VERSION 5.7 ;
  NOWIREEXTENSIONATPIN ON ;
  DIVIDERCHAR "/" ;
  BUSBITCHARS "[]" ;
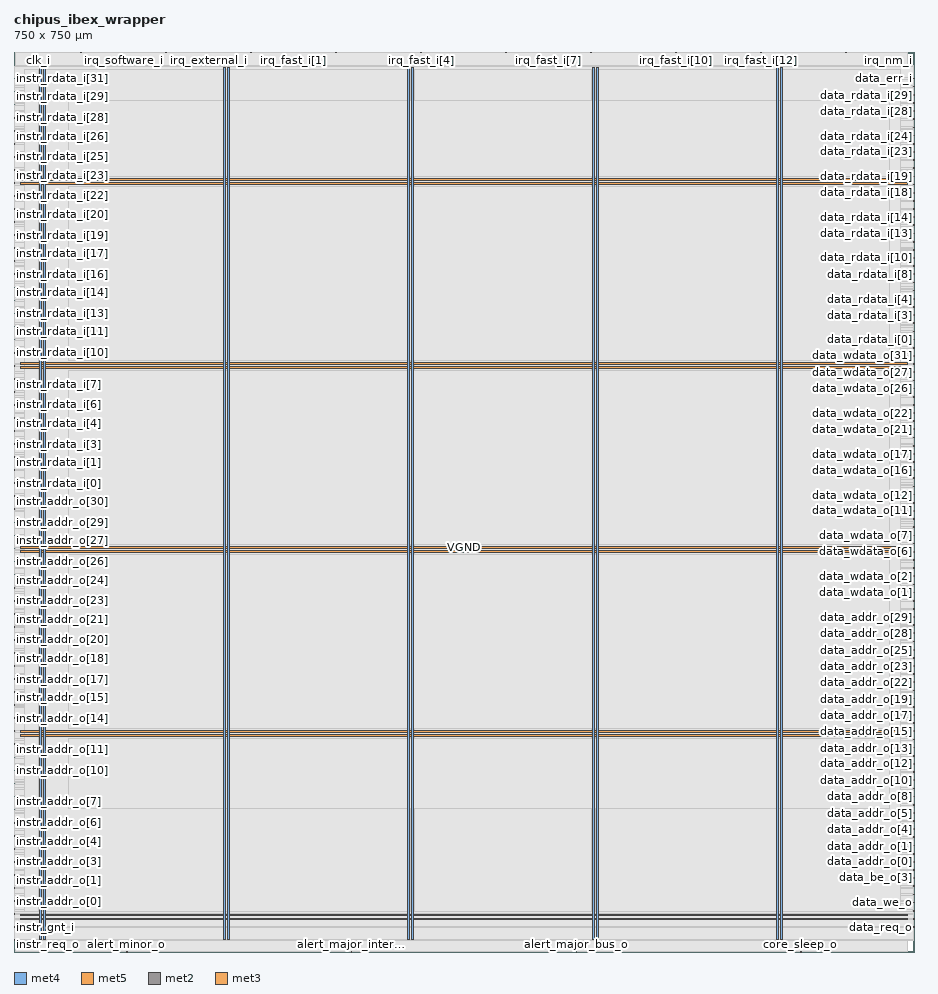
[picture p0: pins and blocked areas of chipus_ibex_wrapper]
MACRO chipus_ibex_wrapper
  CLASS BLOCK ;
  FOREIGN chipus_ibex_wrapper ;
  ORIGIN 0.000 0.000 ;
  SIZE 750.000 BY 750.000 ;
  PIN VGND
    DIRECTION INOUT ;
    USE GROUND ;
    PORT
      LAYER met4 ;
        RECT 24.340 10.640 25.940 737.360 ;
    END
    PORT
      LAYER met4 ;
        RECT 177.940 10.640 179.540 737.360 ;
    END
    PORT
      LAYER met4 ;
        RECT 331.540 10.640 333.140 737.360 ;
    END
    PORT
      LAYER met4 ;
        RECT 485.140 10.640 486.740 737.360 ;
    END
    PORT
      LAYER met4 ;
        RECT 638.740 10.640 640.340 737.360 ;
    END
    PORT
      LAYER met5 ;
        RECT 5.520 30.030 744.280 31.630 ;
    END
    PORT
      LAYER met5 ;
        RECT 5.520 183.210 744.280 184.810 ;
    END
    PORT
      LAYER met5 ;
        RECT 5.520 336.390 744.280 337.990 ;
    END
    PORT
      LAYER met5 ;
        RECT 5.520 489.570 744.280 491.170 ;
    END
    PORT
      LAYER met5 ;
        RECT 5.520 642.750 744.280 644.350 ;
    END
  END VGND
  PIN VPWR
    DIRECTION INOUT ;
    USE POWER ;
    PORT
      LAYER met4 ;
        RECT 21.040 10.640 22.640 737.360 ;
    END
    PORT
      LAYER met4 ;
        RECT 174.640 10.640 176.240 737.360 ;
    END
    PORT
      LAYER met4 ;
        RECT 328.240 10.640 329.840 737.360 ;
    END
    PORT
      LAYER met4 ;
        RECT 481.840 10.640 483.440 737.360 ;
    END
    PORT
      LAYER met4 ;
        RECT 635.440 10.640 637.040 737.360 ;
    END
    PORT
      LAYER met5 ;
        RECT 5.520 26.730 744.280 28.330 ;
    END
    PORT
      LAYER met5 ;
        RECT 5.520 179.910 744.280 181.510 ;
    END
    PORT
      LAYER met5 ;
        RECT 5.520 333.090 744.280 334.690 ;
    END
    PORT
      LAYER met5 ;
        RECT 5.520 486.270 744.280 487.870 ;
    END
    PORT
      LAYER met5 ;
        RECT 5.520 639.450 744.280 641.050 ;
    END
  END VPWR
  PIN alert_major_bus_o
    DIRECTION OUTPUT ;
    USE SIGNAL ;
    PORT
      LAYER met2 ;
        RECT 468.370 0.000 468.650 0.280 ;
    END
  END alert_major_bus_o
  PIN alert_major_internal_o
    DIRECTION OUTPUT ;
    USE SIGNAL ;
    PORT
      LAYER met2 ;
        RECT 281.150 0.000 281.430 0.280 ;
    END
  END alert_major_internal_o
  PIN alert_minor_o
    DIRECTION OUTPUT ;
    USE SIGNAL ;
    PORT
      LAYER met2 ;
        RECT 93.930 0.000 94.210 0.280 ;
    END
  END alert_minor_o
  PIN clk_i
    DIRECTION INPUT ;
    USE SIGNAL ;
    ANTENNAGATEAREA 1.704000 ;
    PORT
      LAYER met2 ;
        RECT 20.330 749.720 20.610 750.000 ;
    END
  END clk_i
  PIN core_sleep_o
    DIRECTION OUTPUT ;
    USE SIGNAL ;
    ANTENNADIFFAREA 0.702900 ;
    PORT
      LAYER met2 ;
        RECT 655.590 0.000 655.870 0.280 ;
    END
  END core_sleep_o
  PIN data_addr_o[0]
    DIRECTION OUTPUT ;
    USE SIGNAL ;
    PORT
      LAYER met3 ;
        RECT 749.400 74.840 750.000 75.440 ;
    END
  END data_addr_o[0]
  PIN data_addr_o[10]
    DIRECTION OUTPUT ;
    USE SIGNAL ;
    ANTENNADIFFAREA 0.702900 ;
    PORT
      LAYER met3 ;
        RECT 749.400 142.840 750.000 143.440 ;
    END
  END data_addr_o[10]
  PIN data_addr_o[11]
    DIRECTION OUTPUT ;
    USE SIGNAL ;
    ANTENNADIFFAREA 0.702900 ;
    PORT
      LAYER met3 ;
        RECT 749.400 149.640 750.000 150.240 ;
    END
  END data_addr_o[11]
  PIN data_addr_o[12]
    DIRECTION OUTPUT ;
    USE SIGNAL ;
    ANTENNADIFFAREA 0.702900 ;
    PORT
      LAYER met3 ;
        RECT 749.400 156.440 750.000 157.040 ;
    END
  END data_addr_o[12]
  PIN data_addr_o[13]
    DIRECTION OUTPUT ;
    USE SIGNAL ;
    ANTENNADIFFAREA 0.702900 ;
    PORT
      LAYER met3 ;
        RECT 749.400 163.240 750.000 163.840 ;
    END
  END data_addr_o[13]
  PIN data_addr_o[14]
    DIRECTION OUTPUT ;
    USE SIGNAL ;
    ANTENNADIFFAREA 0.702900 ;
    PORT
      LAYER met3 ;
        RECT 749.400 170.040 750.000 170.640 ;
    END
  END data_addr_o[14]
  PIN data_addr_o[15]
    DIRECTION OUTPUT ;
    USE SIGNAL ;
    ANTENNADIFFAREA 0.702900 ;
    PORT
      LAYER met3 ;
        RECT 749.400 176.840 750.000 177.440 ;
    END
  END data_addr_o[15]
  PIN data_addr_o[16]
    DIRECTION OUTPUT ;
    USE SIGNAL ;
    ANTENNADIFFAREA 0.702900 ;
    PORT
      LAYER met3 ;
        RECT 749.400 183.640 750.000 184.240 ;
    END
  END data_addr_o[16]
  PIN data_addr_o[17]
    DIRECTION OUTPUT ;
    USE SIGNAL ;
    ANTENNADIFFAREA 0.702900 ;
    PORT
      LAYER met3 ;
        RECT 749.400 190.440 750.000 191.040 ;
    END
  END data_addr_o[17]
  PIN data_addr_o[18]
    DIRECTION OUTPUT ;
    USE SIGNAL ;
    ANTENNADIFFAREA 0.702900 ;
    PORT
      LAYER met3 ;
        RECT 749.400 197.240 750.000 197.840 ;
    END
  END data_addr_o[18]
  PIN data_addr_o[19]
    DIRECTION OUTPUT ;
    USE SIGNAL ;
    ANTENNADIFFAREA 0.702900 ;
    PORT
      LAYER met3 ;
        RECT 749.400 204.040 750.000 204.640 ;
    END
  END data_addr_o[19]
  PIN data_addr_o[1]
    DIRECTION OUTPUT ;
    USE SIGNAL ;
    PORT
      LAYER met3 ;
        RECT 749.400 81.640 750.000 82.240 ;
    END
  END data_addr_o[1]
  PIN data_addr_o[20]
    DIRECTION OUTPUT ;
    USE SIGNAL ;
    ANTENNADIFFAREA 0.702900 ;
    PORT
      LAYER met3 ;
        RECT 749.400 210.840 750.000 211.440 ;
    END
  END data_addr_o[20]
  PIN data_addr_o[21]
    DIRECTION OUTPUT ;
    USE SIGNAL ;
    ANTENNADIFFAREA 0.702900 ;
    PORT
      LAYER met3 ;
        RECT 749.400 217.640 750.000 218.240 ;
    END
  END data_addr_o[21]
  PIN data_addr_o[22]
    DIRECTION OUTPUT ;
    USE SIGNAL ;
    ANTENNADIFFAREA 0.702900 ;
    PORT
      LAYER met3 ;
        RECT 749.400 224.440 750.000 225.040 ;
    END
  END data_addr_o[22]
  PIN data_addr_o[23]
    DIRECTION OUTPUT ;
    USE SIGNAL ;
    ANTENNADIFFAREA 0.702900 ;
    PORT
      LAYER met3 ;
        RECT 749.400 231.240 750.000 231.840 ;
    END
  END data_addr_o[23]
  PIN data_addr_o[24]
    DIRECTION OUTPUT ;
    USE SIGNAL ;
    ANTENNADIFFAREA 0.702900 ;
    PORT
      LAYER met3 ;
        RECT 749.400 238.040 750.000 238.640 ;
    END
  END data_addr_o[24]
  PIN data_addr_o[25]
    DIRECTION OUTPUT ;
    USE SIGNAL ;
    ANTENNADIFFAREA 0.702900 ;
    PORT
      LAYER met3 ;
        RECT 749.400 244.840 750.000 245.440 ;
    END
  END data_addr_o[25]
  PIN data_addr_o[26]
    DIRECTION OUTPUT ;
    USE SIGNAL ;
    ANTENNADIFFAREA 0.702900 ;
    PORT
      LAYER met3 ;
        RECT 749.400 251.640 750.000 252.240 ;
    END
  END data_addr_o[26]
  PIN data_addr_o[27]
    DIRECTION OUTPUT ;
    USE SIGNAL ;
    ANTENNADIFFAREA 0.702900 ;
    PORT
      LAYER met3 ;
        RECT 749.400 258.440 750.000 259.040 ;
    END
  END data_addr_o[27]
  PIN data_addr_o[28]
    DIRECTION OUTPUT ;
    USE SIGNAL ;
    ANTENNADIFFAREA 0.702900 ;
    PORT
      LAYER met3 ;
        RECT 749.400 265.240 750.000 265.840 ;
    END
  END data_addr_o[28]
  PIN data_addr_o[29]
    DIRECTION OUTPUT ;
    USE SIGNAL ;
    ANTENNADIFFAREA 0.702900 ;
    PORT
      LAYER met3 ;
        RECT 749.400 272.040 750.000 272.640 ;
    END
  END data_addr_o[29]
  PIN data_addr_o[2]
    DIRECTION OUTPUT ;
    USE SIGNAL ;
    ANTENNADIFFAREA 0.702900 ;
    PORT
      LAYER met3 ;
        RECT 749.400 88.440 750.000 89.040 ;
    END
  END data_addr_o[2]
  PIN data_addr_o[30]
    DIRECTION OUTPUT ;
    USE SIGNAL ;
    ANTENNADIFFAREA 0.702900 ;
    PORT
      LAYER met3 ;
        RECT 749.400 278.840 750.000 279.440 ;
    END
  END data_addr_o[30]
  PIN data_addr_o[31]
    DIRECTION OUTPUT ;
    USE SIGNAL ;
    ANTENNADIFFAREA 0.702900 ;
    PORT
      LAYER met3 ;
        RECT 749.400 285.640 750.000 286.240 ;
    END
  END data_addr_o[31]
  PIN data_addr_o[3]
    DIRECTION OUTPUT ;
    USE SIGNAL ;
    ANTENNADIFFAREA 0.702900 ;
    PORT
      LAYER met3 ;
        RECT 749.400 95.240 750.000 95.840 ;
    END
  END data_addr_o[3]
  PIN data_addr_o[4]
    DIRECTION OUTPUT ;
    USE SIGNAL ;
    ANTENNADIFFAREA 0.702900 ;
    PORT
      LAYER met3 ;
        RECT 749.400 102.040 750.000 102.640 ;
    END
  END data_addr_o[4]
  PIN data_addr_o[5]
    DIRECTION OUTPUT ;
    USE SIGNAL ;
    ANTENNADIFFAREA 0.702900 ;
    PORT
      LAYER met3 ;
        RECT 749.400 108.840 750.000 109.440 ;
    END
  END data_addr_o[5]
  PIN data_addr_o[6]
    DIRECTION OUTPUT ;
    USE SIGNAL ;
    ANTENNADIFFAREA 0.702900 ;
    PORT
      LAYER met3 ;
        RECT 749.400 115.640 750.000 116.240 ;
    END
  END data_addr_o[6]
  PIN data_addr_o[7]
    DIRECTION OUTPUT ;
    USE SIGNAL ;
    ANTENNADIFFAREA 0.702900 ;
    PORT
      LAYER met3 ;
        RECT 749.400 122.440 750.000 123.040 ;
    END
  END data_addr_o[7]
  PIN data_addr_o[8]
    DIRECTION OUTPUT ;
    USE SIGNAL ;
    ANTENNADIFFAREA 0.702900 ;
    PORT
      LAYER met3 ;
        RECT 749.400 129.240 750.000 129.840 ;
    END
  END data_addr_o[8]
  PIN data_addr_o[9]
    DIRECTION OUTPUT ;
    USE SIGNAL ;
    ANTENNADIFFAREA 0.702900 ;
    PORT
      LAYER met3 ;
        RECT 749.400 136.040 750.000 136.640 ;
    END
  END data_addr_o[9]
  PIN data_be_o[0]
    DIRECTION OUTPUT ;
    USE SIGNAL ;
    ANTENNADIFFAREA 0.702900 ;
    PORT
      LAYER met3 ;
        RECT 749.400 47.640 750.000 48.240 ;
    END
  END data_be_o[0]
  PIN data_be_o[1]
    DIRECTION OUTPUT ;
    USE SIGNAL ;
    ANTENNADIFFAREA 0.702900 ;
    PORT
      LAYER met3 ;
        RECT 749.400 54.440 750.000 55.040 ;
    END
  END data_be_o[1]
  PIN data_be_o[2]
    DIRECTION OUTPUT ;
    USE SIGNAL ;
    ANTENNADIFFAREA 0.702900 ;
    PORT
      LAYER met3 ;
        RECT 749.400 61.240 750.000 61.840 ;
    END
  END data_be_o[2]
  PIN data_be_o[3]
    DIRECTION OUTPUT ;
    USE SIGNAL ;
    ANTENNADIFFAREA 0.702900 ;
    PORT
      LAYER met3 ;
        RECT 749.400 68.040 750.000 68.640 ;
    END
  END data_be_o[3]
  PIN data_err_i
    DIRECTION INPUT ;
    USE SIGNAL ;
    ANTENNAGATEAREA 0.159000 ;
    PORT
      LAYER met3 ;
        RECT 749.400 727.640 750.000 728.240 ;
    END
  END data_err_i
  PIN data_gnt_i
    DIRECTION INPUT ;
    USE SIGNAL ;
    ANTENNAGATEAREA 0.159000 ;
    PORT
      LAYER met3 ;
        RECT 749.400 27.240 750.000 27.840 ;
    END
  END data_gnt_i
  PIN data_rdata_i[0]
    DIRECTION INPUT ;
    USE SIGNAL ;
    ANTENNAGATEAREA 0.213000 ;
    PORT
      LAYER met3 ;
        RECT 749.400 510.040 750.000 510.640 ;
    END
  END data_rdata_i[0]
  PIN data_rdata_i[10]
    DIRECTION INPUT ;
    USE SIGNAL ;
    ANTENNAGATEAREA 0.213000 ;
    PORT
      LAYER met3 ;
        RECT 749.400 578.040 750.000 578.640 ;
    END
  END data_rdata_i[10]
  PIN data_rdata_i[11]
    DIRECTION INPUT ;
    USE SIGNAL ;
    ANTENNAGATEAREA 0.213000 ;
    PORT
      LAYER met3 ;
        RECT 749.400 584.840 750.000 585.440 ;
    END
  END data_rdata_i[11]
  PIN data_rdata_i[12]
    DIRECTION INPUT ;
    USE SIGNAL ;
    ANTENNAGATEAREA 0.213000 ;
    PORT
      LAYER met3 ;
        RECT 749.400 591.640 750.000 592.240 ;
    END
  END data_rdata_i[12]
  PIN data_rdata_i[13]
    DIRECTION INPUT ;
    USE SIGNAL ;
    ANTENNAGATEAREA 0.213000 ;
    PORT
      LAYER met3 ;
        RECT 749.400 598.440 750.000 599.040 ;
    END
  END data_rdata_i[13]
  PIN data_rdata_i[14]
    DIRECTION INPUT ;
    USE SIGNAL ;
    ANTENNAGATEAREA 0.213000 ;
    PORT
      LAYER met3 ;
        RECT 749.400 605.240 750.000 605.840 ;
    END
  END data_rdata_i[14]
  PIN data_rdata_i[15]
    DIRECTION INPUT ;
    USE SIGNAL ;
    ANTENNAGATEAREA 0.213000 ;
    PORT
      LAYER met3 ;
        RECT 749.400 612.040 750.000 612.640 ;
    END
  END data_rdata_i[15]
  PIN data_rdata_i[16]
    DIRECTION INPUT ;
    USE SIGNAL ;
    ANTENNAGATEAREA 0.213000 ;
    PORT
      LAYER met3 ;
        RECT 749.400 618.840 750.000 619.440 ;
    END
  END data_rdata_i[16]
  PIN data_rdata_i[17]
    DIRECTION INPUT ;
    USE SIGNAL ;
    ANTENNAGATEAREA 0.213000 ;
    PORT
      LAYER met3 ;
        RECT 749.400 625.640 750.000 626.240 ;
    END
  END data_rdata_i[17]
  PIN data_rdata_i[18]
    DIRECTION INPUT ;
    USE SIGNAL ;
    ANTENNAGATEAREA 0.213000 ;
    PORT
      LAYER met3 ;
        RECT 749.400 632.440 750.000 633.040 ;
    END
  END data_rdata_i[18]
  PIN data_rdata_i[19]
    DIRECTION INPUT ;
    USE SIGNAL ;
    ANTENNAGATEAREA 0.213000 ;
    PORT
      LAYER met3 ;
        RECT 749.400 639.240 750.000 639.840 ;
    END
  END data_rdata_i[19]
  PIN data_rdata_i[1]
    DIRECTION INPUT ;
    USE SIGNAL ;
    ANTENNAGATEAREA 0.213000 ;
    PORT
      LAYER met3 ;
        RECT 749.400 516.840 750.000 517.440 ;
    END
  END data_rdata_i[1]
  PIN data_rdata_i[20]
    DIRECTION INPUT ;
    USE SIGNAL ;
    ANTENNAGATEAREA 0.213000 ;
    PORT
      LAYER met3 ;
        RECT 749.400 646.040 750.000 646.640 ;
    END
  END data_rdata_i[20]
  PIN data_rdata_i[21]
    DIRECTION INPUT ;
    USE SIGNAL ;
    ANTENNAGATEAREA 0.213000 ;
    PORT
      LAYER met3 ;
        RECT 749.400 652.840 750.000 653.440 ;
    END
  END data_rdata_i[21]
  PIN data_rdata_i[22]
    DIRECTION INPUT ;
    USE SIGNAL ;
    ANTENNAGATEAREA 0.213000 ;
    PORT
      LAYER met3 ;
        RECT 749.400 659.640 750.000 660.240 ;
    END
  END data_rdata_i[22]
  PIN data_rdata_i[23]
    DIRECTION INPUT ;
    USE SIGNAL ;
    ANTENNAGATEAREA 0.213000 ;
    PORT
      LAYER met3 ;
        RECT 749.400 666.440 750.000 667.040 ;
    END
  END data_rdata_i[23]
  PIN data_rdata_i[24]
    DIRECTION INPUT ;
    USE SIGNAL ;
    ANTENNAGATEAREA 0.213000 ;
    PORT
      LAYER met3 ;
        RECT 749.400 673.240 750.000 673.840 ;
    END
  END data_rdata_i[24]
  PIN data_rdata_i[25]
    DIRECTION INPUT ;
    USE SIGNAL ;
    ANTENNAGATEAREA 0.213000 ;
    PORT
      LAYER met3 ;
        RECT 749.400 680.040 750.000 680.640 ;
    END
  END data_rdata_i[25]
  PIN data_rdata_i[26]
    DIRECTION INPUT ;
    USE SIGNAL ;
    ANTENNAGATEAREA 0.213000 ;
    PORT
      LAYER met3 ;
        RECT 749.400 686.840 750.000 687.440 ;
    END
  END data_rdata_i[26]
  PIN data_rdata_i[27]
    DIRECTION INPUT ;
    USE SIGNAL ;
    ANTENNAGATEAREA 0.213000 ;
    PORT
      LAYER met3 ;
        RECT 749.400 693.640 750.000 694.240 ;
    END
  END data_rdata_i[27]
  PIN data_rdata_i[28]
    DIRECTION INPUT ;
    USE SIGNAL ;
    ANTENNAGATEAREA 0.213000 ;
    PORT
      LAYER met3 ;
        RECT 749.400 700.440 750.000 701.040 ;
    END
  END data_rdata_i[28]
  PIN data_rdata_i[29]
    DIRECTION INPUT ;
    USE SIGNAL ;
    ANTENNAGATEAREA 0.213000 ;
    PORT
      LAYER met3 ;
        RECT 749.400 707.240 750.000 707.840 ;
    END
  END data_rdata_i[29]
  PIN data_rdata_i[2]
    DIRECTION INPUT ;
    USE SIGNAL ;
    ANTENNAGATEAREA 0.213000 ;
    PORT
      LAYER met3 ;
        RECT 749.400 523.640 750.000 524.240 ;
    END
  END data_rdata_i[2]
  PIN data_rdata_i[30]
    DIRECTION INPUT ;
    USE SIGNAL ;
    ANTENNAGATEAREA 0.213000 ;
    PORT
      LAYER met3 ;
        RECT 749.400 714.040 750.000 714.640 ;
    END
  END data_rdata_i[30]
  PIN data_rdata_i[31]
    DIRECTION INPUT ;
    USE SIGNAL ;
    ANTENNAGATEAREA 0.213000 ;
    PORT
      LAYER met3 ;
        RECT 749.400 720.840 750.000 721.440 ;
    END
  END data_rdata_i[31]
  PIN data_rdata_i[3]
    DIRECTION INPUT ;
    USE SIGNAL ;
    ANTENNAGATEAREA 0.213000 ;
    PORT
      LAYER met3 ;
        RECT 749.400 530.440 750.000 531.040 ;
    END
  END data_rdata_i[3]
  PIN data_rdata_i[4]
    DIRECTION INPUT ;
    USE SIGNAL ;
    ANTENNAGATEAREA 0.213000 ;
    PORT
      LAYER met3 ;
        RECT 749.400 537.240 750.000 537.840 ;
    END
  END data_rdata_i[4]
  PIN data_rdata_i[5]
    DIRECTION INPUT ;
    USE SIGNAL ;
    ANTENNAGATEAREA 0.213000 ;
    PORT
      LAYER met3 ;
        RECT 749.400 544.040 750.000 544.640 ;
    END
  END data_rdata_i[5]
  PIN data_rdata_i[6]
    DIRECTION INPUT ;
    USE SIGNAL ;
    ANTENNAGATEAREA 0.213000 ;
    PORT
      LAYER met3 ;
        RECT 749.400 550.840 750.000 551.440 ;
    END
  END data_rdata_i[6]
  PIN data_rdata_i[7]
    DIRECTION INPUT ;
    USE SIGNAL ;
    ANTENNAGATEAREA 0.213000 ;
    PORT
      LAYER met3 ;
        RECT 749.400 557.640 750.000 558.240 ;
    END
  END data_rdata_i[7]
  PIN data_rdata_i[8]
    DIRECTION INPUT ;
    USE SIGNAL ;
    ANTENNAGATEAREA 0.213000 ;
    PORT
      LAYER met3 ;
        RECT 749.400 564.440 750.000 565.040 ;
    END
  END data_rdata_i[8]
  PIN data_rdata_i[9]
    DIRECTION INPUT ;
    USE SIGNAL ;
    ANTENNAGATEAREA 0.213000 ;
    PORT
      LAYER met3 ;
        RECT 749.400 571.240 750.000 571.840 ;
    END
  END data_rdata_i[9]
  PIN data_req_o
    DIRECTION OUTPUT ;
    USE SIGNAL ;
    ANTENNADIFFAREA 0.702900 ;
    PORT
      LAYER met3 ;
        RECT 749.400 20.440 750.000 21.040 ;
    END
  END data_req_o
  PIN data_rvalid_i
    DIRECTION INPUT ;
    USE SIGNAL ;
    ANTENNAGATEAREA 0.159000 ;
    PORT
      LAYER met3 ;
        RECT 749.400 34.040 750.000 34.640 ;
    END
  END data_rvalid_i
  PIN data_wdata_o[0]
    DIRECTION OUTPUT ;
    USE SIGNAL ;
    ANTENNADIFFAREA 0.702900 ;
    PORT
      LAYER met3 ;
        RECT 749.400 292.440 750.000 293.040 ;
    END
  END data_wdata_o[0]
  PIN data_wdata_o[10]
    DIRECTION OUTPUT ;
    USE SIGNAL ;
    ANTENNADIFFAREA 0.702900 ;
    PORT
      LAYER met3 ;
        RECT 749.400 360.440 750.000 361.040 ;
    END
  END data_wdata_o[10]
  PIN data_wdata_o[11]
    DIRECTION OUTPUT ;
    USE SIGNAL ;
    ANTENNADIFFAREA 0.702900 ;
    PORT
      LAYER met3 ;
        RECT 749.400 367.240 750.000 367.840 ;
    END
  END data_wdata_o[11]
  PIN data_wdata_o[12]
    DIRECTION OUTPUT ;
    USE SIGNAL ;
    ANTENNADIFFAREA 0.702900 ;
    PORT
      LAYER met3 ;
        RECT 749.400 374.040 750.000 374.640 ;
    END
  END data_wdata_o[12]
  PIN data_wdata_o[13]
    DIRECTION OUTPUT ;
    USE SIGNAL ;
    ANTENNADIFFAREA 0.702900 ;
    PORT
      LAYER met3 ;
        RECT 749.400 380.840 750.000 381.440 ;
    END
  END data_wdata_o[13]
  PIN data_wdata_o[14]
    DIRECTION OUTPUT ;
    USE SIGNAL ;
    ANTENNADIFFAREA 0.702900 ;
    PORT
      LAYER met3 ;
        RECT 749.400 387.640 750.000 388.240 ;
    END
  END data_wdata_o[14]
  PIN data_wdata_o[15]
    DIRECTION OUTPUT ;
    USE SIGNAL ;
    ANTENNADIFFAREA 0.702900 ;
    PORT
      LAYER met3 ;
        RECT 749.400 394.440 750.000 395.040 ;
    END
  END data_wdata_o[15]
  PIN data_wdata_o[16]
    DIRECTION OUTPUT ;
    USE SIGNAL ;
    ANTENNADIFFAREA 0.702900 ;
    PORT
      LAYER met3 ;
        RECT 749.400 401.240 750.000 401.840 ;
    END
  END data_wdata_o[16]
  PIN data_wdata_o[17]
    DIRECTION OUTPUT ;
    USE SIGNAL ;
    ANTENNADIFFAREA 0.702900 ;
    PORT
      LAYER met3 ;
        RECT 749.400 408.040 750.000 408.640 ;
    END
  END data_wdata_o[17]
  PIN data_wdata_o[18]
    DIRECTION OUTPUT ;
    USE SIGNAL ;
    ANTENNADIFFAREA 0.702900 ;
    PORT
      LAYER met3 ;
        RECT 749.400 414.840 750.000 415.440 ;
    END
  END data_wdata_o[18]
  PIN data_wdata_o[19]
    DIRECTION OUTPUT ;
    USE SIGNAL ;
    ANTENNADIFFAREA 0.702900 ;
    PORT
      LAYER met3 ;
        RECT 749.400 421.640 750.000 422.240 ;
    END
  END data_wdata_o[19]
  PIN data_wdata_o[1]
    DIRECTION OUTPUT ;
    USE SIGNAL ;
    ANTENNADIFFAREA 0.702900 ;
    PORT
      LAYER met3 ;
        RECT 749.400 299.240 750.000 299.840 ;
    END
  END data_wdata_o[1]
  PIN data_wdata_o[20]
    DIRECTION OUTPUT ;
    USE SIGNAL ;
    ANTENNADIFFAREA 0.702900 ;
    PORT
      LAYER met3 ;
        RECT 749.400 428.440 750.000 429.040 ;
    END
  END data_wdata_o[20]
  PIN data_wdata_o[21]
    DIRECTION OUTPUT ;
    USE SIGNAL ;
    ANTENNADIFFAREA 0.702900 ;
    PORT
      LAYER met3 ;
        RECT 749.400 435.240 750.000 435.840 ;
    END
  END data_wdata_o[21]
  PIN data_wdata_o[22]
    DIRECTION OUTPUT ;
    USE SIGNAL ;
    ANTENNADIFFAREA 0.702900 ;
    PORT
      LAYER met3 ;
        RECT 749.400 442.040 750.000 442.640 ;
    END
  END data_wdata_o[22]
  PIN data_wdata_o[23]
    DIRECTION OUTPUT ;
    USE SIGNAL ;
    ANTENNADIFFAREA 0.702900 ;
    PORT
      LAYER met3 ;
        RECT 749.400 448.840 750.000 449.440 ;
    END
  END data_wdata_o[23]
  PIN data_wdata_o[24]
    DIRECTION OUTPUT ;
    USE SIGNAL ;
    ANTENNADIFFAREA 0.702900 ;
    PORT
      LAYER met3 ;
        RECT 749.400 455.640 750.000 456.240 ;
    END
  END data_wdata_o[24]
  PIN data_wdata_o[25]
    DIRECTION OUTPUT ;
    USE SIGNAL ;
    ANTENNADIFFAREA 0.702900 ;
    PORT
      LAYER met3 ;
        RECT 749.400 462.440 750.000 463.040 ;
    END
  END data_wdata_o[25]
  PIN data_wdata_o[26]
    DIRECTION OUTPUT ;
    USE SIGNAL ;
    ANTENNADIFFAREA 0.702900 ;
    PORT
      LAYER met3 ;
        RECT 749.400 469.240 750.000 469.840 ;
    END
  END data_wdata_o[26]
  PIN data_wdata_o[27]
    DIRECTION OUTPUT ;
    USE SIGNAL ;
    ANTENNADIFFAREA 0.702900 ;
    PORT
      LAYER met3 ;
        RECT 749.400 476.040 750.000 476.640 ;
    END
  END data_wdata_o[27]
  PIN data_wdata_o[28]
    DIRECTION OUTPUT ;
    USE SIGNAL ;
    ANTENNADIFFAREA 0.702900 ;
    PORT
      LAYER met3 ;
        RECT 749.400 482.840 750.000 483.440 ;
    END
  END data_wdata_o[28]
  PIN data_wdata_o[29]
    DIRECTION OUTPUT ;
    USE SIGNAL ;
    ANTENNADIFFAREA 0.702900 ;
    PORT
      LAYER met3 ;
        RECT 749.400 489.640 750.000 490.240 ;
    END
  END data_wdata_o[29]
  PIN data_wdata_o[2]
    DIRECTION OUTPUT ;
    USE SIGNAL ;
    ANTENNADIFFAREA 0.702900 ;
    PORT
      LAYER met3 ;
        RECT 749.400 306.040 750.000 306.640 ;
    END
  END data_wdata_o[2]
  PIN data_wdata_o[30]
    DIRECTION OUTPUT ;
    USE SIGNAL ;
    ANTENNADIFFAREA 0.702900 ;
    PORT
      LAYER met3 ;
        RECT 749.400 496.440 750.000 497.040 ;
    END
  END data_wdata_o[30]
  PIN data_wdata_o[31]
    DIRECTION OUTPUT ;
    USE SIGNAL ;
    ANTENNADIFFAREA 0.702900 ;
    PORT
      LAYER met3 ;
        RECT 749.400 503.240 750.000 503.840 ;
    END
  END data_wdata_o[31]
  PIN data_wdata_o[3]
    DIRECTION OUTPUT ;
    USE SIGNAL ;
    ANTENNADIFFAREA 0.702900 ;
    PORT
      LAYER met3 ;
        RECT 749.400 312.840 750.000 313.440 ;
    END
  END data_wdata_o[3]
  PIN data_wdata_o[4]
    DIRECTION OUTPUT ;
    USE SIGNAL ;
    ANTENNADIFFAREA 0.702900 ;
    PORT
      LAYER met3 ;
        RECT 749.400 319.640 750.000 320.240 ;
    END
  END data_wdata_o[4]
  PIN data_wdata_o[5]
    DIRECTION OUTPUT ;
    USE SIGNAL ;
    ANTENNADIFFAREA 0.702900 ;
    PORT
      LAYER met3 ;
        RECT 749.400 326.440 750.000 327.040 ;
    END
  END data_wdata_o[5]
  PIN data_wdata_o[6]
    DIRECTION OUTPUT ;
    USE SIGNAL ;
    ANTENNADIFFAREA 0.702900 ;
    PORT
      LAYER met3 ;
        RECT 749.400 333.240 750.000 333.840 ;
    END
  END data_wdata_o[6]
  PIN data_wdata_o[7]
    DIRECTION OUTPUT ;
    USE SIGNAL ;
    ANTENNADIFFAREA 0.702900 ;
    PORT
      LAYER met3 ;
        RECT 749.400 340.040 750.000 340.640 ;
    END
  END data_wdata_o[7]
  PIN data_wdata_o[8]
    DIRECTION OUTPUT ;
    USE SIGNAL ;
    ANTENNADIFFAREA 0.702900 ;
    PORT
      LAYER met3 ;
        RECT 749.400 346.840 750.000 347.440 ;
    END
  END data_wdata_o[8]
  PIN data_wdata_o[9]
    DIRECTION OUTPUT ;
    USE SIGNAL ;
    ANTENNADIFFAREA 0.702900 ;
    PORT
      LAYER met3 ;
        RECT 749.400 353.640 750.000 354.240 ;
    END
  END data_wdata_o[9]
  PIN data_we_o
    DIRECTION OUTPUT ;
    USE SIGNAL ;
    ANTENNADIFFAREA 0.702900 ;
    PORT
      LAYER met3 ;
        RECT 749.400 40.840 750.000 41.440 ;
    END
  END data_we_o
  PIN instr_addr_o[0]
    DIRECTION OUTPUT ;
    USE SIGNAL ;
    PORT
      LAYER met3 ;
        RECT 0.000 42.200 0.600 42.800 ;
    END
  END instr_addr_o[0]
  PIN instr_addr_o[10]
    DIRECTION OUTPUT ;
    USE SIGNAL ;
    ANTENNADIFFAREA 0.702900 ;
    PORT
      LAYER met3 ;
        RECT 0.000 151.000 0.600 151.600 ;
    END
  END instr_addr_o[10]
  PIN instr_addr_o[11]
    DIRECTION OUTPUT ;
    USE SIGNAL ;
    ANTENNADIFFAREA 0.702900 ;
    PORT
      LAYER met3 ;
        RECT 0.000 161.880 0.600 162.480 ;
    END
  END instr_addr_o[11]
  PIN instr_addr_o[12]
    DIRECTION OUTPUT ;
    USE SIGNAL ;
    ANTENNADIFFAREA 0.702900 ;
    PORT
      LAYER met3 ;
        RECT 0.000 172.760 0.600 173.360 ;
    END
  END instr_addr_o[12]
  PIN instr_addr_o[13]
    DIRECTION OUTPUT ;
    USE SIGNAL ;
    ANTENNADIFFAREA 0.702900 ;
    PORT
      LAYER met3 ;
        RECT 0.000 183.640 0.600 184.240 ;
    END
  END instr_addr_o[13]
  PIN instr_addr_o[14]
    DIRECTION OUTPUT ;
    USE SIGNAL ;
    ANTENNADIFFAREA 0.702900 ;
    PORT
      LAYER met3 ;
        RECT 0.000 194.520 0.600 195.120 ;
    END
  END instr_addr_o[14]
  PIN instr_addr_o[15]
    DIRECTION OUTPUT ;
    USE SIGNAL ;
    ANTENNADIFFAREA 0.702900 ;
    PORT
      LAYER met3 ;
        RECT 0.000 205.400 0.600 206.000 ;
    END
  END instr_addr_o[15]
  PIN instr_addr_o[16]
    DIRECTION OUTPUT ;
    USE SIGNAL ;
    ANTENNADIFFAREA 0.702900 ;
    PORT
      LAYER met3 ;
        RECT 0.000 216.280 0.600 216.880 ;
    END
  END instr_addr_o[16]
  PIN instr_addr_o[17]
    DIRECTION OUTPUT ;
    USE SIGNAL ;
    ANTENNADIFFAREA 0.702900 ;
    PORT
      LAYER met3 ;
        RECT 0.000 227.160 0.600 227.760 ;
    END
  END instr_addr_o[17]
  PIN instr_addr_o[18]
    DIRECTION OUTPUT ;
    USE SIGNAL ;
    ANTENNADIFFAREA 0.702900 ;
    PORT
      LAYER met3 ;
        RECT 0.000 238.040 0.600 238.640 ;
    END
  END instr_addr_o[18]
  PIN instr_addr_o[19]
    DIRECTION OUTPUT ;
    USE SIGNAL ;
    ANTENNADIFFAREA 0.702900 ;
    PORT
      LAYER met3 ;
        RECT 0.000 248.920 0.600 249.520 ;
    END
  END instr_addr_o[19]
  PIN instr_addr_o[1]
    DIRECTION OUTPUT ;
    USE SIGNAL ;
    PORT
      LAYER met3 ;
        RECT 0.000 53.080 0.600 53.680 ;
    END
  END instr_addr_o[1]
  PIN instr_addr_o[20]
    DIRECTION OUTPUT ;
    USE SIGNAL ;
    ANTENNADIFFAREA 0.702900 ;
    PORT
      LAYER met3 ;
        RECT 0.000 259.800 0.600 260.400 ;
    END
  END instr_addr_o[20]
  PIN instr_addr_o[21]
    DIRECTION OUTPUT ;
    USE SIGNAL ;
    ANTENNADIFFAREA 0.702900 ;
    PORT
      LAYER met3 ;
        RECT 0.000 270.680 0.600 271.280 ;
    END
  END instr_addr_o[21]
  PIN instr_addr_o[22]
    DIRECTION OUTPUT ;
    USE SIGNAL ;
    ANTENNADIFFAREA 0.702900 ;
    PORT
      LAYER met3 ;
        RECT 0.000 281.560 0.600 282.160 ;
    END
  END instr_addr_o[22]
  PIN instr_addr_o[23]
    DIRECTION OUTPUT ;
    USE SIGNAL ;
    ANTENNADIFFAREA 0.702900 ;
    PORT
      LAYER met3 ;
        RECT 0.000 292.440 0.600 293.040 ;
    END
  END instr_addr_o[23]
  PIN instr_addr_o[24]
    DIRECTION OUTPUT ;
    USE SIGNAL ;
    ANTENNADIFFAREA 0.702900 ;
    PORT
      LAYER met3 ;
        RECT 0.000 303.320 0.600 303.920 ;
    END
  END instr_addr_o[24]
  PIN instr_addr_o[25]
    DIRECTION OUTPUT ;
    USE SIGNAL ;
    ANTENNADIFFAREA 0.702900 ;
    PORT
      LAYER met3 ;
        RECT 0.000 314.200 0.600 314.800 ;
    END
  END instr_addr_o[25]
  PIN instr_addr_o[26]
    DIRECTION OUTPUT ;
    USE SIGNAL ;
    ANTENNADIFFAREA 0.702900 ;
    PORT
      LAYER met3 ;
        RECT 0.000 325.080 0.600 325.680 ;
    END
  END instr_addr_o[26]
  PIN instr_addr_o[27]
    DIRECTION OUTPUT ;
    USE SIGNAL ;
    ANTENNADIFFAREA 0.702900 ;
    PORT
      LAYER met3 ;
        RECT 0.000 335.960 0.600 336.560 ;
    END
  END instr_addr_o[27]
  PIN instr_addr_o[28]
    DIRECTION OUTPUT ;
    USE SIGNAL ;
    ANTENNADIFFAREA 0.702900 ;
    PORT
      LAYER met3 ;
        RECT 0.000 346.840 0.600 347.440 ;
    END
  END instr_addr_o[28]
  PIN instr_addr_o[29]
    DIRECTION OUTPUT ;
    USE SIGNAL ;
    ANTENNADIFFAREA 0.702900 ;
    PORT
      LAYER met3 ;
        RECT 0.000 357.720 0.600 358.320 ;
    END
  END instr_addr_o[29]
  PIN instr_addr_o[2]
    DIRECTION OUTPUT ;
    USE SIGNAL ;
    ANTENNADIFFAREA 0.702900 ;
    PORT
      LAYER met3 ;
        RECT 0.000 63.960 0.600 64.560 ;
    END
  END instr_addr_o[2]
  PIN instr_addr_o[30]
    DIRECTION OUTPUT ;
    USE SIGNAL ;
    ANTENNADIFFAREA 0.702900 ;
    PORT
      LAYER met3 ;
        RECT 0.000 368.600 0.600 369.200 ;
    END
  END instr_addr_o[30]
  PIN instr_addr_o[31]
    DIRECTION OUTPUT ;
    USE SIGNAL ;
    ANTENNADIFFAREA 0.702900 ;
    PORT
      LAYER met3 ;
        RECT 0.000 379.480 0.600 380.080 ;
    END
  END instr_addr_o[31]
  PIN instr_addr_o[3]
    DIRECTION OUTPUT ;
    USE SIGNAL ;
    ANTENNADIFFAREA 0.702900 ;
    PORT
      LAYER met3 ;
        RECT 0.000 74.840 0.600 75.440 ;
    END
  END instr_addr_o[3]
  PIN instr_addr_o[4]
    DIRECTION OUTPUT ;
    USE SIGNAL ;
    ANTENNADIFFAREA 0.702900 ;
    PORT
      LAYER met3 ;
        RECT 0.000 85.720 0.600 86.320 ;
    END
  END instr_addr_o[4]
  PIN instr_addr_o[5]
    DIRECTION OUTPUT ;
    USE SIGNAL ;
    ANTENNADIFFAREA 0.702900 ;
    PORT
      LAYER met3 ;
        RECT 0.000 96.600 0.600 97.200 ;
    END
  END instr_addr_o[5]
  PIN instr_addr_o[6]
    DIRECTION OUTPUT ;
    USE SIGNAL ;
    ANTENNADIFFAREA 0.702900 ;
    PORT
      LAYER met3 ;
        RECT 0.000 107.480 0.600 108.080 ;
    END
  END instr_addr_o[6]
  PIN instr_addr_o[7]
    DIRECTION OUTPUT ;
    USE SIGNAL ;
    ANTENNADIFFAREA 0.702900 ;
    PORT
      LAYER met3 ;
        RECT 0.000 118.360 0.600 118.960 ;
    END
  END instr_addr_o[7]
  PIN instr_addr_o[8]
    DIRECTION OUTPUT ;
    USE SIGNAL ;
    ANTENNADIFFAREA 0.702900 ;
    PORT
      LAYER met3 ;
        RECT 0.000 129.240 0.600 129.840 ;
    END
  END instr_addr_o[8]
  PIN instr_addr_o[9]
    DIRECTION OUTPUT ;
    USE SIGNAL ;
    ANTENNADIFFAREA 0.702900 ;
    PORT
      LAYER met3 ;
        RECT 0.000 140.120 0.600 140.720 ;
    END
  END instr_addr_o[9]
  PIN instr_err_i
    DIRECTION INPUT ;
    USE SIGNAL ;
    ANTENNAGATEAREA 0.213000 ;
    PORT
      LAYER met3 ;
        RECT 0.000 738.520 0.600 739.120 ;
    END
  END instr_err_i
  PIN instr_gnt_i
    DIRECTION INPUT ;
    USE SIGNAL ;
    ANTENNAGATEAREA 0.213000 ;
    PORT
      LAYER met3 ;
        RECT 0.000 20.440 0.600 21.040 ;
    END
  END instr_gnt_i
  PIN instr_rdata_i[0]
    DIRECTION INPUT ;
    USE SIGNAL ;
    ANTENNAGATEAREA 0.213000 ;
    PORT
      LAYER met3 ;
        RECT 0.000 390.360 0.600 390.960 ;
    END
  END instr_rdata_i[0]
  PIN instr_rdata_i[10]
    DIRECTION INPUT ;
    USE SIGNAL ;
    ANTENNAGATEAREA 0.213000 ;
    PORT
      LAYER met3 ;
        RECT 0.000 499.160 0.600 499.760 ;
    END
  END instr_rdata_i[10]
  PIN instr_rdata_i[11]
    DIRECTION INPUT ;
    USE SIGNAL ;
    ANTENNAGATEAREA 0.213000 ;
    PORT
      LAYER met3 ;
        RECT 0.000 510.040 0.600 510.640 ;
    END
  END instr_rdata_i[11]
  PIN instr_rdata_i[12]
    DIRECTION INPUT ;
    USE SIGNAL ;
    ANTENNAGATEAREA 0.213000 ;
    PORT
      LAYER met3 ;
        RECT 0.000 520.920 0.600 521.520 ;
    END
  END instr_rdata_i[12]
  PIN instr_rdata_i[13]
    DIRECTION INPUT ;
    USE SIGNAL ;
    ANTENNAGATEAREA 0.213000 ;
    PORT
      LAYER met3 ;
        RECT 0.000 531.800 0.600 532.400 ;
    END
  END instr_rdata_i[13]
  PIN instr_rdata_i[14]
    DIRECTION INPUT ;
    USE SIGNAL ;
    ANTENNAGATEAREA 0.213000 ;
    PORT
      LAYER met3 ;
        RECT 0.000 542.680 0.600 543.280 ;
    END
  END instr_rdata_i[14]
  PIN instr_rdata_i[15]
    DIRECTION INPUT ;
    USE SIGNAL ;
    ANTENNAGATEAREA 0.213000 ;
    PORT
      LAYER met3 ;
        RECT 0.000 553.560 0.600 554.160 ;
    END
  END instr_rdata_i[15]
  PIN instr_rdata_i[16]
    DIRECTION INPUT ;
    USE SIGNAL ;
    ANTENNAGATEAREA 0.213000 ;
    PORT
      LAYER met3 ;
        RECT 0.000 564.440 0.600 565.040 ;
    END
  END instr_rdata_i[16]
  PIN instr_rdata_i[17]
    DIRECTION INPUT ;
    USE SIGNAL ;
    ANTENNAGATEAREA 0.213000 ;
    PORT
      LAYER met3 ;
        RECT 0.000 575.320 0.600 575.920 ;
    END
  END instr_rdata_i[17]
  PIN instr_rdata_i[18]
    DIRECTION INPUT ;
    USE SIGNAL ;
    ANTENNAGATEAREA 0.213000 ;
    PORT
      LAYER met3 ;
        RECT 0.000 586.200 0.600 586.800 ;
    END
  END instr_rdata_i[18]
  PIN instr_rdata_i[19]
    DIRECTION INPUT ;
    USE SIGNAL ;
    ANTENNAGATEAREA 0.213000 ;
    PORT
      LAYER met3 ;
        RECT 0.000 597.080 0.600 597.680 ;
    END
  END instr_rdata_i[19]
  PIN instr_rdata_i[1]
    DIRECTION INPUT ;
    USE SIGNAL ;
    ANTENNAGATEAREA 0.213000 ;
    PORT
      LAYER met3 ;
        RECT 0.000 401.240 0.600 401.840 ;
    END
  END instr_rdata_i[1]
  PIN instr_rdata_i[20]
    DIRECTION INPUT ;
    USE SIGNAL ;
    ANTENNAGATEAREA 0.213000 ;
    PORT
      LAYER met3 ;
        RECT 0.000 607.960 0.600 608.560 ;
    END
  END instr_rdata_i[20]
  PIN instr_rdata_i[21]
    DIRECTION INPUT ;
    USE SIGNAL ;
    ANTENNAGATEAREA 0.213000 ;
    PORT
      LAYER met3 ;
        RECT 0.000 618.840 0.600 619.440 ;
    END
  END instr_rdata_i[21]
  PIN instr_rdata_i[22]
    DIRECTION INPUT ;
    USE SIGNAL ;
    ANTENNAGATEAREA 0.213000 ;
    PORT
      LAYER met3 ;
        RECT 0.000 629.720 0.600 630.320 ;
    END
  END instr_rdata_i[22]
  PIN instr_rdata_i[23]
    DIRECTION INPUT ;
    USE SIGNAL ;
    ANTENNAGATEAREA 0.213000 ;
    PORT
      LAYER met3 ;
        RECT 0.000 640.600 0.600 641.200 ;
    END
  END instr_rdata_i[23]
  PIN instr_rdata_i[24]
    DIRECTION INPUT ;
    USE SIGNAL ;
    ANTENNAGATEAREA 0.213000 ;
    PORT
      LAYER met3 ;
        RECT 0.000 651.480 0.600 652.080 ;
    END
  END instr_rdata_i[24]
  PIN instr_rdata_i[25]
    DIRECTION INPUT ;
    USE SIGNAL ;
    ANTENNAGATEAREA 0.213000 ;
    PORT
      LAYER met3 ;
        RECT 0.000 662.360 0.600 662.960 ;
    END
  END instr_rdata_i[25]
  PIN instr_rdata_i[26]
    DIRECTION INPUT ;
    USE SIGNAL ;
    ANTENNAGATEAREA 0.213000 ;
    PORT
      LAYER met3 ;
        RECT 0.000 673.240 0.600 673.840 ;
    END
  END instr_rdata_i[26]
  PIN instr_rdata_i[27]
    DIRECTION INPUT ;
    USE SIGNAL ;
    ANTENNAGATEAREA 0.213000 ;
    PORT
      LAYER met3 ;
        RECT 0.000 684.120 0.600 684.720 ;
    END
  END instr_rdata_i[27]
  PIN instr_rdata_i[28]
    DIRECTION INPUT ;
    USE SIGNAL ;
    ANTENNAGATEAREA 0.213000 ;
    PORT
      LAYER met3 ;
        RECT 0.000 695.000 0.600 695.600 ;
    END
  END instr_rdata_i[28]
  PIN instr_rdata_i[29]
    DIRECTION INPUT ;
    USE SIGNAL ;
    ANTENNAGATEAREA 0.213000 ;
    PORT
      LAYER met3 ;
        RECT 0.000 705.880 0.600 706.480 ;
    END
  END instr_rdata_i[29]
  PIN instr_rdata_i[2]
    DIRECTION INPUT ;
    USE SIGNAL ;
    ANTENNAGATEAREA 0.213000 ;
    PORT
      LAYER met3 ;
        RECT 0.000 412.120 0.600 412.720 ;
    END
  END instr_rdata_i[2]
  PIN instr_rdata_i[30]
    DIRECTION INPUT ;
    USE SIGNAL ;
    ANTENNAGATEAREA 0.213000 ;
    PORT
      LAYER met3 ;
        RECT 0.000 716.760 0.600 717.360 ;
    END
  END instr_rdata_i[30]
  PIN instr_rdata_i[31]
    DIRECTION INPUT ;
    USE SIGNAL ;
    ANTENNAGATEAREA 0.213000 ;
    PORT
      LAYER met3 ;
        RECT 0.000 727.640 0.600 728.240 ;
    END
  END instr_rdata_i[31]
  PIN instr_rdata_i[3]
    DIRECTION INPUT ;
    USE SIGNAL ;
    ANTENNAGATEAREA 0.213000 ;
    PORT
      LAYER met3 ;
        RECT 0.000 423.000 0.600 423.600 ;
    END
  END instr_rdata_i[3]
  PIN instr_rdata_i[4]
    DIRECTION INPUT ;
    USE SIGNAL ;
    ANTENNAGATEAREA 0.213000 ;
    PORT
      LAYER met3 ;
        RECT 0.000 433.880 0.600 434.480 ;
    END
  END instr_rdata_i[4]
  PIN instr_rdata_i[5]
    DIRECTION INPUT ;
    USE SIGNAL ;
    ANTENNAGATEAREA 0.213000 ;
    PORT
      LAYER met3 ;
        RECT 0.000 444.760 0.600 445.360 ;
    END
  END instr_rdata_i[5]
  PIN instr_rdata_i[6]
    DIRECTION INPUT ;
    USE SIGNAL ;
    ANTENNAGATEAREA 0.213000 ;
    PORT
      LAYER met3 ;
        RECT 0.000 455.640 0.600 456.240 ;
    END
  END instr_rdata_i[6]
  PIN instr_rdata_i[7]
    DIRECTION INPUT ;
    USE SIGNAL ;
    ANTENNAGATEAREA 0.213000 ;
    PORT
      LAYER met3 ;
        RECT 0.000 466.520 0.600 467.120 ;
    END
  END instr_rdata_i[7]
  PIN instr_rdata_i[8]
    DIRECTION INPUT ;
    USE SIGNAL ;
    ANTENNAGATEAREA 0.213000 ;
    PORT
      LAYER met3 ;
        RECT 0.000 477.400 0.600 478.000 ;
    END
  END instr_rdata_i[8]
  PIN instr_rdata_i[9]
    DIRECTION INPUT ;
    USE SIGNAL ;
    ANTENNAGATEAREA 0.213000 ;
    PORT
      LAYER met3 ;
        RECT 0.000 488.280 0.600 488.880 ;
    END
  END instr_rdata_i[9]
  PIN instr_req_o
    DIRECTION OUTPUT ;
    USE SIGNAL ;
    ANTENNADIFFAREA 0.702900 ;
    PORT
      LAYER met3 ;
        RECT 0.000 9.560 0.600 10.160 ;
    END
  END instr_req_o
  PIN instr_rvalid_i
    DIRECTION INPUT ;
    USE SIGNAL ;
    ANTENNAGATEAREA 0.196500 ;
    PORT
      LAYER met3 ;
        RECT 0.000 31.320 0.600 31.920 ;
    END
  END instr_rvalid_i
  PIN irq_external_i
    DIRECTION INPUT ;
    USE SIGNAL ;
    ANTENNAGATEAREA 0.196500 ;
    PORT
      LAYER met2 ;
        RECT 162.010 749.720 162.290 750.000 ;
    END
  END irq_external_i
  PIN irq_fast_i[0]
    DIRECTION INPUT ;
    USE SIGNAL ;
    ANTENNAGATEAREA 0.213000 ;
    PORT
      LAYER met2 ;
        RECT 197.430 749.720 197.710 750.000 ;
    END
  END irq_fast_i[0]
  PIN irq_fast_i[10]
    DIRECTION INPUT ;
    USE SIGNAL ;
    ANTENNAGATEAREA 0.159000 ;
    PORT
      LAYER met2 ;
        RECT 551.630 749.720 551.910 750.000 ;
    END
  END irq_fast_i[10]
  PIN irq_fast_i[11]
    DIRECTION INPUT ;
    USE SIGNAL ;
    ANTENNAGATEAREA 0.159000 ;
    PORT
      LAYER met2 ;
        RECT 587.050 749.720 587.330 750.000 ;
    END
  END irq_fast_i[11]
  PIN irq_fast_i[12]
    DIRECTION INPUT ;
    USE SIGNAL ;
    ANTENNAGATEAREA 0.213000 ;
    PORT
      LAYER met2 ;
        RECT 622.470 749.720 622.750 750.000 ;
    END
  END irq_fast_i[12]
  PIN irq_fast_i[13]
    DIRECTION INPUT ;
    USE SIGNAL ;
    ANTENNAGATEAREA 0.159000 ;
    PORT
      LAYER met2 ;
        RECT 657.890 749.720 658.170 750.000 ;
    END
  END irq_fast_i[13]
  PIN irq_fast_i[14]
    DIRECTION INPUT ;
    USE SIGNAL ;
    ANTENNAGATEAREA 0.159000 ;
    PORT
      LAYER met2 ;
        RECT 693.310 749.720 693.590 750.000 ;
    END
  END irq_fast_i[14]
  PIN irq_fast_i[1]
    DIRECTION INPUT ;
    USE SIGNAL ;
    ANTENNAGATEAREA 0.213000 ;
    PORT
      LAYER met2 ;
        RECT 232.850 749.720 233.130 750.000 ;
    END
  END irq_fast_i[1]
  PIN irq_fast_i[2]
    DIRECTION INPUT ;
    USE SIGNAL ;
    ANTENNAGATEAREA 0.213000 ;
    PORT
      LAYER met2 ;
        RECT 268.270 749.720 268.550 750.000 ;
    END
  END irq_fast_i[2]
  PIN irq_fast_i[3]
    DIRECTION INPUT ;
    USE SIGNAL ;
    ANTENNAGATEAREA 0.213000 ;
    PORT
      LAYER met2 ;
        RECT 303.690 749.720 303.970 750.000 ;
    END
  END irq_fast_i[3]
  PIN irq_fast_i[4]
    DIRECTION INPUT ;
    USE SIGNAL ;
    ANTENNAGATEAREA 0.196500 ;
    PORT
      LAYER met2 ;
        RECT 339.110 749.720 339.390 750.000 ;
    END
  END irq_fast_i[4]
  PIN irq_fast_i[5]
    DIRECTION INPUT ;
    USE SIGNAL ;
    ANTENNAGATEAREA 0.196500 ;
    PORT
      LAYER met2 ;
        RECT 374.530 749.720 374.810 750.000 ;
    END
  END irq_fast_i[5]
  PIN irq_fast_i[6]
    DIRECTION INPUT ;
    USE SIGNAL ;
    ANTENNAGATEAREA 0.196500 ;
    PORT
      LAYER met2 ;
        RECT 409.950 749.720 410.230 750.000 ;
    END
  END irq_fast_i[6]
  PIN irq_fast_i[7]
    DIRECTION INPUT ;
    USE SIGNAL ;
    ANTENNAGATEAREA 0.159000 ;
    PORT
      LAYER met2 ;
        RECT 445.370 749.720 445.650 750.000 ;
    END
  END irq_fast_i[7]
  PIN irq_fast_i[8]
    DIRECTION INPUT ;
    USE SIGNAL ;
    ANTENNAGATEAREA 0.159000 ;
    PORT
      LAYER met2 ;
        RECT 480.790 749.720 481.070 750.000 ;
    END
  END irq_fast_i[8]
  PIN irq_fast_i[9]
    DIRECTION INPUT ;
    USE SIGNAL ;
    ANTENNAGATEAREA 0.159000 ;
    PORT
      LAYER met2 ;
        RECT 516.210 749.720 516.490 750.000 ;
    END
  END irq_fast_i[9]
  PIN irq_nm_i
    DIRECTION INPUT ;
    USE SIGNAL ;
    ANTENNAGATEAREA 0.159000 ;
    PORT
      LAYER met2 ;
        RECT 728.730 749.720 729.010 750.000 ;
    END
  END irq_nm_i
  PIN irq_software_i
    DIRECTION INPUT ;
    USE SIGNAL ;
    ANTENNAGATEAREA 0.213000 ;
    PORT
      LAYER met2 ;
        RECT 91.170 749.720 91.450 750.000 ;
    END
  END irq_software_i
  PIN irq_timer_i
    DIRECTION INPUT ;
    USE SIGNAL ;
    ANTENNAGATEAREA 0.213000 ;
    PORT
      LAYER met2 ;
        RECT 126.590 749.720 126.870 750.000 ;
    END
  END irq_timer_i
  PIN rst_ni
    DIRECTION INPUT ;
    USE SIGNAL ;
    ANTENNAGATEAREA 0.213000 ;
    PORT
      LAYER met2 ;
        RECT 55.750 749.720 56.030 750.000 ;
    END
  END rst_ni
  OBS
      LAYER nwell ;
        RECT 5.330 10.795 744.470 737.310 ;
      LAYER li1 ;
        RECT 5.520 10.795 744.280 737.205 ;
      LAYER met1 ;
        RECT 1.450 10.640 744.670 737.360 ;
      LAYER met2 ;
        RECT 1.470 749.440 20.050 749.720 ;
        RECT 20.890 749.440 55.470 749.720 ;
        RECT 56.310 749.440 90.890 749.720 ;
        RECT 91.730 749.440 126.310 749.720 ;
        RECT 127.150 749.440 161.730 749.720 ;
        RECT 162.570 749.440 197.150 749.720 ;
        RECT 197.990 749.440 232.570 749.720 ;
        RECT 233.410 749.440 267.990 749.720 ;
        RECT 268.830 749.440 303.410 749.720 ;
        RECT 304.250 749.440 338.830 749.720 ;
        RECT 339.670 749.440 374.250 749.720 ;
        RECT 375.090 749.440 409.670 749.720 ;
        RECT 410.510 749.440 445.090 749.720 ;
        RECT 445.930 749.440 480.510 749.720 ;
        RECT 481.350 749.440 515.930 749.720 ;
        RECT 516.770 749.440 551.350 749.720 ;
        RECT 552.190 749.440 586.770 749.720 ;
        RECT 587.610 749.440 622.190 749.720 ;
        RECT 623.030 749.440 657.610 749.720 ;
        RECT 658.450 749.440 693.030 749.720 ;
        RECT 693.870 749.440 728.450 749.720 ;
        RECT 729.290 749.440 744.650 749.720 ;
        RECT 1.470 0.560 744.650 749.440 ;
        RECT 1.470 0.280 93.650 0.560 ;
        RECT 94.490 0.280 280.870 0.560 ;
        RECT 281.710 0.280 468.090 0.560 ;
        RECT 468.930 0.280 655.310 0.560 ;
        RECT 656.150 0.280 744.650 0.560 ;
      LAYER met3 ;
        RECT 1.000 738.120 749.400 738.985 ;
        RECT 0.600 728.640 749.400 738.120 ;
        RECT 1.000 727.240 749.000 728.640 ;
        RECT 0.600 721.840 749.400 727.240 ;
        RECT 0.600 720.440 749.000 721.840 ;
        RECT 0.600 717.760 749.400 720.440 ;
        RECT 1.000 716.360 749.400 717.760 ;
        RECT 0.600 715.040 749.400 716.360 ;
        RECT 0.600 713.640 749.000 715.040 ;
        RECT 0.600 708.240 749.400 713.640 ;
        RECT 0.600 706.880 749.000 708.240 ;
        RECT 1.000 706.840 749.000 706.880 ;
        RECT 1.000 705.480 749.400 706.840 ;
        RECT 0.600 701.440 749.400 705.480 ;
        RECT 0.600 700.040 749.000 701.440 ;
        RECT 0.600 696.000 749.400 700.040 ;
        RECT 1.000 694.640 749.400 696.000 ;
        RECT 1.000 694.600 749.000 694.640 ;
        RECT 0.600 693.240 749.000 694.600 ;
        RECT 0.600 687.840 749.400 693.240 ;
        RECT 0.600 686.440 749.000 687.840 ;
        RECT 0.600 685.120 749.400 686.440 ;
        RECT 1.000 683.720 749.400 685.120 ;
        RECT 0.600 681.040 749.400 683.720 ;
        RECT 0.600 679.640 749.000 681.040 ;
        RECT 0.600 674.240 749.400 679.640 ;
        RECT 1.000 672.840 749.000 674.240 ;
        RECT 0.600 667.440 749.400 672.840 ;
        RECT 0.600 666.040 749.000 667.440 ;
        RECT 0.600 663.360 749.400 666.040 ;
        RECT 1.000 661.960 749.400 663.360 ;
        RECT 0.600 660.640 749.400 661.960 ;
        RECT 0.600 659.240 749.000 660.640 ;
        RECT 0.600 653.840 749.400 659.240 ;
        RECT 0.600 652.480 749.000 653.840 ;
        RECT 1.000 652.440 749.000 652.480 ;
        RECT 1.000 651.080 749.400 652.440 ;
        RECT 0.600 647.040 749.400 651.080 ;
        RECT 0.600 645.640 749.000 647.040 ;
        RECT 0.600 641.600 749.400 645.640 ;
        RECT 1.000 640.240 749.400 641.600 ;
        RECT 1.000 640.200 749.000 640.240 ;
        RECT 0.600 638.840 749.000 640.200 ;
        RECT 0.600 633.440 749.400 638.840 ;
        RECT 0.600 632.040 749.000 633.440 ;
        RECT 0.600 630.720 749.400 632.040 ;
        RECT 1.000 629.320 749.400 630.720 ;
        RECT 0.600 626.640 749.400 629.320 ;
        RECT 0.600 625.240 749.000 626.640 ;
        RECT 0.600 619.840 749.400 625.240 ;
        RECT 1.000 618.440 749.000 619.840 ;
        RECT 0.600 613.040 749.400 618.440 ;
        RECT 0.600 611.640 749.000 613.040 ;
        RECT 0.600 608.960 749.400 611.640 ;
        RECT 1.000 607.560 749.400 608.960 ;
        RECT 0.600 606.240 749.400 607.560 ;
        RECT 0.600 604.840 749.000 606.240 ;
        RECT 0.600 599.440 749.400 604.840 ;
        RECT 0.600 598.080 749.000 599.440 ;
        RECT 1.000 598.040 749.000 598.080 ;
        RECT 1.000 596.680 749.400 598.040 ;
        RECT 0.600 592.640 749.400 596.680 ;
        RECT 0.600 591.240 749.000 592.640 ;
        RECT 0.600 587.200 749.400 591.240 ;
        RECT 1.000 585.840 749.400 587.200 ;
        RECT 1.000 585.800 749.000 585.840 ;
        RECT 0.600 584.440 749.000 585.800 ;
        RECT 0.600 579.040 749.400 584.440 ;
        RECT 0.600 577.640 749.000 579.040 ;
        RECT 0.600 576.320 749.400 577.640 ;
        RECT 1.000 574.920 749.400 576.320 ;
        RECT 0.600 572.240 749.400 574.920 ;
        RECT 0.600 570.840 749.000 572.240 ;
        RECT 0.600 565.440 749.400 570.840 ;
        RECT 1.000 564.040 749.000 565.440 ;
        RECT 0.600 558.640 749.400 564.040 ;
        RECT 0.600 557.240 749.000 558.640 ;
        RECT 0.600 554.560 749.400 557.240 ;
        RECT 1.000 553.160 749.400 554.560 ;
        RECT 0.600 551.840 749.400 553.160 ;
        RECT 0.600 550.440 749.000 551.840 ;
        RECT 0.600 545.040 749.400 550.440 ;
        RECT 0.600 543.680 749.000 545.040 ;
        RECT 1.000 543.640 749.000 543.680 ;
        RECT 1.000 542.280 749.400 543.640 ;
        RECT 0.600 538.240 749.400 542.280 ;
        RECT 0.600 536.840 749.000 538.240 ;
        RECT 0.600 532.800 749.400 536.840 ;
        RECT 1.000 531.440 749.400 532.800 ;
        RECT 1.000 531.400 749.000 531.440 ;
        RECT 0.600 530.040 749.000 531.400 ;
        RECT 0.600 524.640 749.400 530.040 ;
        RECT 0.600 523.240 749.000 524.640 ;
        RECT 0.600 521.920 749.400 523.240 ;
        RECT 1.000 520.520 749.400 521.920 ;
        RECT 0.600 517.840 749.400 520.520 ;
        RECT 0.600 516.440 749.000 517.840 ;
        RECT 0.600 511.040 749.400 516.440 ;
        RECT 1.000 509.640 749.000 511.040 ;
        RECT 0.600 504.240 749.400 509.640 ;
        RECT 0.600 502.840 749.000 504.240 ;
        RECT 0.600 500.160 749.400 502.840 ;
        RECT 1.000 498.760 749.400 500.160 ;
        RECT 0.600 497.440 749.400 498.760 ;
        RECT 0.600 496.040 749.000 497.440 ;
        RECT 0.600 490.640 749.400 496.040 ;
        RECT 0.600 489.280 749.000 490.640 ;
        RECT 1.000 489.240 749.000 489.280 ;
        RECT 1.000 487.880 749.400 489.240 ;
        RECT 0.600 483.840 749.400 487.880 ;
        RECT 0.600 482.440 749.000 483.840 ;
        RECT 0.600 478.400 749.400 482.440 ;
        RECT 1.000 477.040 749.400 478.400 ;
        RECT 1.000 477.000 749.000 477.040 ;
        RECT 0.600 475.640 749.000 477.000 ;
        RECT 0.600 470.240 749.400 475.640 ;
        RECT 0.600 468.840 749.000 470.240 ;
        RECT 0.600 467.520 749.400 468.840 ;
        RECT 1.000 466.120 749.400 467.520 ;
        RECT 0.600 463.440 749.400 466.120 ;
        RECT 0.600 462.040 749.000 463.440 ;
        RECT 0.600 456.640 749.400 462.040 ;
        RECT 1.000 455.240 749.000 456.640 ;
        RECT 0.600 449.840 749.400 455.240 ;
        RECT 0.600 448.440 749.000 449.840 ;
        RECT 0.600 445.760 749.400 448.440 ;
        RECT 1.000 444.360 749.400 445.760 ;
        RECT 0.600 443.040 749.400 444.360 ;
        RECT 0.600 441.640 749.000 443.040 ;
        RECT 0.600 436.240 749.400 441.640 ;
        RECT 0.600 434.880 749.000 436.240 ;
        RECT 1.000 434.840 749.000 434.880 ;
        RECT 1.000 433.480 749.400 434.840 ;
        RECT 0.600 429.440 749.400 433.480 ;
        RECT 0.600 428.040 749.000 429.440 ;
        RECT 0.600 424.000 749.400 428.040 ;
        RECT 1.000 422.640 749.400 424.000 ;
        RECT 1.000 422.600 749.000 422.640 ;
        RECT 0.600 421.240 749.000 422.600 ;
        RECT 0.600 415.840 749.400 421.240 ;
        RECT 0.600 414.440 749.000 415.840 ;
        RECT 0.600 413.120 749.400 414.440 ;
        RECT 1.000 411.720 749.400 413.120 ;
        RECT 0.600 409.040 749.400 411.720 ;
        RECT 0.600 407.640 749.000 409.040 ;
        RECT 0.600 402.240 749.400 407.640 ;
        RECT 1.000 400.840 749.000 402.240 ;
        RECT 0.600 395.440 749.400 400.840 ;
        RECT 0.600 394.040 749.000 395.440 ;
        RECT 0.600 391.360 749.400 394.040 ;
        RECT 1.000 389.960 749.400 391.360 ;
        RECT 0.600 388.640 749.400 389.960 ;
        RECT 0.600 387.240 749.000 388.640 ;
        RECT 0.600 381.840 749.400 387.240 ;
        RECT 0.600 380.480 749.000 381.840 ;
        RECT 1.000 380.440 749.000 380.480 ;
        RECT 1.000 379.080 749.400 380.440 ;
        RECT 0.600 375.040 749.400 379.080 ;
        RECT 0.600 373.640 749.000 375.040 ;
        RECT 0.600 369.600 749.400 373.640 ;
        RECT 1.000 368.240 749.400 369.600 ;
        RECT 1.000 368.200 749.000 368.240 ;
        RECT 0.600 366.840 749.000 368.200 ;
        RECT 0.600 361.440 749.400 366.840 ;
        RECT 0.600 360.040 749.000 361.440 ;
        RECT 0.600 358.720 749.400 360.040 ;
        RECT 1.000 357.320 749.400 358.720 ;
        RECT 0.600 354.640 749.400 357.320 ;
        RECT 0.600 353.240 749.000 354.640 ;
        RECT 0.600 347.840 749.400 353.240 ;
        RECT 1.000 346.440 749.000 347.840 ;
        RECT 0.600 341.040 749.400 346.440 ;
        RECT 0.600 339.640 749.000 341.040 ;
        RECT 0.600 336.960 749.400 339.640 ;
        RECT 1.000 335.560 749.400 336.960 ;
        RECT 0.600 334.240 749.400 335.560 ;
        RECT 0.600 332.840 749.000 334.240 ;
        RECT 0.600 327.440 749.400 332.840 ;
        RECT 0.600 326.080 749.000 327.440 ;
        RECT 1.000 326.040 749.000 326.080 ;
        RECT 1.000 324.680 749.400 326.040 ;
        RECT 0.600 320.640 749.400 324.680 ;
        RECT 0.600 319.240 749.000 320.640 ;
        RECT 0.600 315.200 749.400 319.240 ;
        RECT 1.000 313.840 749.400 315.200 ;
        RECT 1.000 313.800 749.000 313.840 ;
        RECT 0.600 312.440 749.000 313.800 ;
        RECT 0.600 307.040 749.400 312.440 ;
        RECT 0.600 305.640 749.000 307.040 ;
        RECT 0.600 304.320 749.400 305.640 ;
        RECT 1.000 302.920 749.400 304.320 ;
        RECT 0.600 300.240 749.400 302.920 ;
        RECT 0.600 298.840 749.000 300.240 ;
        RECT 0.600 293.440 749.400 298.840 ;
        RECT 1.000 292.040 749.000 293.440 ;
        RECT 0.600 286.640 749.400 292.040 ;
        RECT 0.600 285.240 749.000 286.640 ;
        RECT 0.600 282.560 749.400 285.240 ;
        RECT 1.000 281.160 749.400 282.560 ;
        RECT 0.600 279.840 749.400 281.160 ;
        RECT 0.600 278.440 749.000 279.840 ;
        RECT 0.600 273.040 749.400 278.440 ;
        RECT 0.600 271.680 749.000 273.040 ;
        RECT 1.000 271.640 749.000 271.680 ;
        RECT 1.000 270.280 749.400 271.640 ;
        RECT 0.600 266.240 749.400 270.280 ;
        RECT 0.600 264.840 749.000 266.240 ;
        RECT 0.600 260.800 749.400 264.840 ;
        RECT 1.000 259.440 749.400 260.800 ;
        RECT 1.000 259.400 749.000 259.440 ;
        RECT 0.600 258.040 749.000 259.400 ;
        RECT 0.600 252.640 749.400 258.040 ;
        RECT 0.600 251.240 749.000 252.640 ;
        RECT 0.600 249.920 749.400 251.240 ;
        RECT 1.000 248.520 749.400 249.920 ;
        RECT 0.600 245.840 749.400 248.520 ;
        RECT 0.600 244.440 749.000 245.840 ;
        RECT 0.600 239.040 749.400 244.440 ;
        RECT 1.000 237.640 749.000 239.040 ;
        RECT 0.600 232.240 749.400 237.640 ;
        RECT 0.600 230.840 749.000 232.240 ;
        RECT 0.600 228.160 749.400 230.840 ;
        RECT 1.000 226.760 749.400 228.160 ;
        RECT 0.600 225.440 749.400 226.760 ;
        RECT 0.600 224.040 749.000 225.440 ;
        RECT 0.600 218.640 749.400 224.040 ;
        RECT 0.600 217.280 749.000 218.640 ;
        RECT 1.000 217.240 749.000 217.280 ;
        RECT 1.000 215.880 749.400 217.240 ;
        RECT 0.600 211.840 749.400 215.880 ;
        RECT 0.600 210.440 749.000 211.840 ;
        RECT 0.600 206.400 749.400 210.440 ;
        RECT 1.000 205.040 749.400 206.400 ;
        RECT 1.000 205.000 749.000 205.040 ;
        RECT 0.600 203.640 749.000 205.000 ;
        RECT 0.600 198.240 749.400 203.640 ;
        RECT 0.600 196.840 749.000 198.240 ;
        RECT 0.600 195.520 749.400 196.840 ;
        RECT 1.000 194.120 749.400 195.520 ;
        RECT 0.600 191.440 749.400 194.120 ;
        RECT 0.600 190.040 749.000 191.440 ;
        RECT 0.600 184.640 749.400 190.040 ;
        RECT 1.000 183.240 749.000 184.640 ;
        RECT 0.600 177.840 749.400 183.240 ;
        RECT 0.600 176.440 749.000 177.840 ;
        RECT 0.600 173.760 749.400 176.440 ;
        RECT 1.000 172.360 749.400 173.760 ;
        RECT 0.600 171.040 749.400 172.360 ;
        RECT 0.600 169.640 749.000 171.040 ;
        RECT 0.600 164.240 749.400 169.640 ;
        RECT 0.600 162.880 749.000 164.240 ;
        RECT 1.000 162.840 749.000 162.880 ;
        RECT 1.000 161.480 749.400 162.840 ;
        RECT 0.600 157.440 749.400 161.480 ;
        RECT 0.600 156.040 749.000 157.440 ;
        RECT 0.600 152.000 749.400 156.040 ;
        RECT 1.000 150.640 749.400 152.000 ;
        RECT 1.000 150.600 749.000 150.640 ;
        RECT 0.600 149.240 749.000 150.600 ;
        RECT 0.600 143.840 749.400 149.240 ;
        RECT 0.600 142.440 749.000 143.840 ;
        RECT 0.600 141.120 749.400 142.440 ;
        RECT 1.000 139.720 749.400 141.120 ;
        RECT 0.600 137.040 749.400 139.720 ;
        RECT 0.600 135.640 749.000 137.040 ;
        RECT 0.600 130.240 749.400 135.640 ;
        RECT 1.000 128.840 749.000 130.240 ;
        RECT 0.600 123.440 749.400 128.840 ;
        RECT 0.600 122.040 749.000 123.440 ;
        RECT 0.600 119.360 749.400 122.040 ;
        RECT 1.000 117.960 749.400 119.360 ;
        RECT 0.600 116.640 749.400 117.960 ;
        RECT 0.600 115.240 749.000 116.640 ;
        RECT 0.600 109.840 749.400 115.240 ;
        RECT 0.600 108.480 749.000 109.840 ;
        RECT 1.000 108.440 749.000 108.480 ;
        RECT 1.000 107.080 749.400 108.440 ;
        RECT 0.600 103.040 749.400 107.080 ;
        RECT 0.600 101.640 749.000 103.040 ;
        RECT 0.600 97.600 749.400 101.640 ;
        RECT 1.000 96.240 749.400 97.600 ;
        RECT 1.000 96.200 749.000 96.240 ;
        RECT 0.600 94.840 749.000 96.200 ;
        RECT 0.600 89.440 749.400 94.840 ;
        RECT 0.600 88.040 749.000 89.440 ;
        RECT 0.600 86.720 749.400 88.040 ;
        RECT 1.000 85.320 749.400 86.720 ;
        RECT 0.600 82.640 749.400 85.320 ;
        RECT 0.600 81.240 749.000 82.640 ;
        RECT 0.600 75.840 749.400 81.240 ;
        RECT 1.000 74.440 749.000 75.840 ;
        RECT 0.600 69.040 749.400 74.440 ;
        RECT 0.600 67.640 749.000 69.040 ;
        RECT 0.600 64.960 749.400 67.640 ;
        RECT 1.000 63.560 749.400 64.960 ;
        RECT 0.600 62.240 749.400 63.560 ;
        RECT 0.600 60.840 749.000 62.240 ;
        RECT 0.600 55.440 749.400 60.840 ;
        RECT 0.600 54.080 749.000 55.440 ;
        RECT 1.000 54.040 749.000 54.080 ;
        RECT 1.000 52.680 749.400 54.040 ;
        RECT 0.600 48.640 749.400 52.680 ;
        RECT 0.600 47.240 749.000 48.640 ;
        RECT 0.600 43.200 749.400 47.240 ;
        RECT 1.000 41.840 749.400 43.200 ;
        RECT 1.000 41.800 749.000 41.840 ;
        RECT 0.600 40.440 749.000 41.800 ;
        RECT 0.600 35.040 749.400 40.440 ;
        RECT 0.600 33.640 749.000 35.040 ;
        RECT 0.600 32.320 749.400 33.640 ;
        RECT 1.000 30.920 749.400 32.320 ;
        RECT 0.600 28.240 749.400 30.920 ;
        RECT 0.600 26.840 749.000 28.240 ;
        RECT 0.600 21.440 749.400 26.840 ;
        RECT 1.000 20.040 749.000 21.440 ;
        RECT 0.600 10.560 749.400 20.040 ;
        RECT 1.000 9.695 749.400 10.560 ;
      LAYER met4 ;
        RECT 8.575 33.495 20.640 735.585 ;
        RECT 23.040 33.495 23.940 735.585 ;
        RECT 26.340 33.495 174.240 735.585 ;
        RECT 176.640 33.495 177.540 735.585 ;
        RECT 179.940 33.495 327.840 735.585 ;
        RECT 330.240 33.495 331.140 735.585 ;
        RECT 333.540 33.495 481.440 735.585 ;
        RECT 483.840 33.495 484.740 735.585 ;
        RECT 487.140 33.495 635.040 735.585 ;
        RECT 637.440 33.495 638.340 735.585 ;
        RECT 640.740 33.495 738.465 735.585 ;
      LAYER met5 ;
        RECT 45.660 645.950 729.900 709.700 ;
        RECT 45.660 492.770 729.900 637.850 ;
        RECT 45.660 339.590 729.900 484.670 ;
        RECT 45.660 186.410 729.900 331.490 ;
        RECT 45.660 119.900 729.900 178.310 ;
  END
END chipus_ibex_wrapper
END LIBRARY

